# LEF file generated by Abstract Generator version 5.5.9 on Apr 28 16:11:38 2004
#
# Contains LEF for all bins.
# Options:   [ ] Antenna
#            [x] Geometry
#            [x] Technology

VERSION 5.7 ;
#NAMESCASESENSITIVE ON ;
BUSBITCHARS "[]" ;
DIVIDERCHAR "/" ;

PROPERTYDEFINITIONS
  LAYER LEF57_SPACING STRING ;
END PROPERTYDEFINITIONS

PROPERTYDEFINITIONS
  LAYER LEF57_SPACINGTABLE STRING ;
END PROPERTYDEFINITIONS

UNITS
  DATABASE MICRONS 2000 ;
END UNITS

USEMINSPACING OBS OFF ;
#USEMINSPACING PIN OFF ;
CLEARANCEMEASURE EUCLIDEAN ;

MANUFACTURINGGRID 0.005 ;

LAYER DIFF 
  TYPE MASTERSLICE ;
END DIFF 

LAYER PO1
  TYPE MASTERSLICE ;
END PO1

LAYER LLHVT
  TYPE IMPLANT ;
  SPACING 0.20  ;
  WIDTH 0.36 ;
END LLHVT

LAYER LLLVT
  TYPE IMPLANT ;
  SPACING 0.20  ;
  WIDTH 0.36 ;
END LLLVT

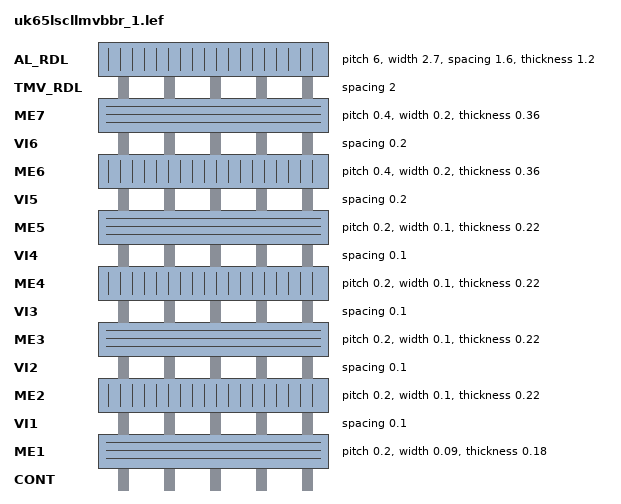
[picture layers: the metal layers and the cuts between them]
LAYER CONT
  TYPE CUT ;
  ANTENNAAREARATIO 10 ;
END CONT

LAYER ME1
  TYPE ROUTING ;
  DIRECTION HORIZONTAL ;
  PITCH 0.20 ;
  OFFSET 0.0 ;
  WIDTH 0.09 ;
  SPACINGTABLE PARALLELRUNLENGTH 0 0.5 2.8 WIDTH 0 0.09 0.09 0.09 WIDTH 0.5 0.09 0.16 0.16 WIDTH 2.8 0.09 0.16 0.3 ;
  MAXWIDTH 12 ;
  RESISTANCE RPERSQ 0.17 ;
  CAPACITANCE CPERSQDIST 3.0334e-04 ;
  EDGECAPACITANCE 1.0635e-04 ;
  THICKNESS 0.18 ;
  ANTENNACUMAREARATIO 5000 ;
  ANTENNACUMDIFFAREARATIO PWL ( ( 0 5000 ) ( 0.095 5000 ) ( 0.1 45045 ) ( 100 90000 ) ) ;
  AREA 0.042 ;
  MINENCLOSEDAREA 0.2 ;
  MINIMUMCUT 2 WIDTH 0.495 WITHIN 0.3 FROMABOVE ;
  MINIMUMCUT 3 WIDTH 0.7 WITHIN 0.3 FROMABOVE ;
  MINIMUMCUT 4 WIDTH 1.495 WITHIN 0.3 FROMABOVE ;
  MINIMUMDENSITY 15 ;
  MAXIMUMDENSITY 80 ;
  DENSITYCHECKWINDOW 50 50 ;
  DENSITYCHECKSTEP 25 ;
  FILLACTIVESPACING 0.8 ;
  MINSTEP 0.045 MAXEDGES 2 ;
  DCCURRENTDENSITY AVERAGE 1.89 ;
  ACCURRENTDENSITY RMS
   FREQUENCY	1 ;
   WIDTH	0.09 0.2 0.5 1.0 2.0 5.0 12.0 ;
   TABLEENTRIES	14.996 11.459 8.638 7.329 6.546 6.015 5.794 ;
END ME1

LAYER VI1
  TYPE CUT ;
  SPACING 0.1 ;
  SPACING 0.11 ADJACENTCUTS 3 WITHIN 0.14 ;
  ANTENNACUMAREARATIO 180 ;
  ANTENNACUMDIFFAREARATIO PWL ( ( 0 180 ) ( 0.095 180 ) ( 0.1 820 ) ( 100 20800 ) ) ;
  DCCURRENTDENSITY AVERAGE 25 ;
END VI1

LAYER ME2
  TYPE ROUTING ;
  DIRECTION VERTICAL ;
  PITCH 0.20 ;
  OFFSET 0.10 ;
  WIDTH 0.10 ;
  SPACINGTABLE PARALLELRUNLENGTH 0 0.5 1.5 WIDTH 0 0.1 0.1 0.1 WIDTH 0.5 0.1 0.16 0.16 WIDTH 2.8 0.1 0.16 0.3 ;
  MAXWIDTH 12 ;
  RESISTANCE RPERSQ 0.15 ;
  CAPACITANCE CPERSQDIST 3.6968e-04 ;
  EDGECAPACITANCE 9.1099e-05 ;
  THICKNESS 0.22 ;
  ANTENNACUMAREARATIO 5000 ;
  ANTENNACUMDIFFAREARATIO PWL ( ( 0 5000 ) ( 0.095 5000 ) ( 0.1 45045 ) ( 100 90000 ) ) ;
  AREA 0.046 ;
  MINENCLOSEDAREA 0.11 ;
  MINIMUMCUT 2 WIDTH 0.495 WITHIN 0.35 ;
  MINIMUMCUT 3 WIDTH 0.7 WITHIN 0.35 ;
  MINIMUMCUT 4 WIDTH 1.495 WITHIN 0.35 ;
  MINIMUMDENSITY 15 ;
  MAXIMUMDENSITY 80 ;
  DENSITYCHECKWINDOW 50 50 ;
  DENSITYCHECKSTEP 25 ;
  FILLACTIVESPACING 0.8 ;
  MINSTEP 0.05 MAXEDGES 2 ;
  DCCURRENTDENSITY AVERAGE 2.31 ;
  ACCURRENTDENSITY RMS
   FREQUENCY	1 ;
   WIDTH	0.1 0.2 0.5 1.0 2.0 5.0 12.0 ;
   TABLEENTRIES	13.518 10.696 7.906 6.544 5.698 5.107 4.854 ;
END ME2

LAYER VI2
  TYPE CUT ;
  SPACING 0.1 ;
  SPACING 0.11 ADJACENTCUTS 3 WITHIN 0.14 ;
  ANTENNACUMAREARATIO 180 ;
  ANTENNACUMDIFFAREARATIO PWL ( ( 0 180 ) ( 0.095 180 ) ( 0.1 820 ) ( 100 20800 ) ) ;
  DCCURRENTDENSITY AVERAGE 25 ;
END VI2

LAYER ME3
  TYPE ROUTING ;
  DIRECTION HORIZONTAL ;
  PITCH 0.20 ;
  OFFSET 0.0 ;
  WIDTH 0.10 ;
  SPACINGTABLE PARALLELRUNLENGTH 0 0.5 1.5 WIDTH 0 0.1 0.1 0.1 WIDTH 0.5 0.1 0.16 0.16 WIDTH 2.8 0.1 0.16 0.3 ;
  MAXWIDTH 12 ;
  RESISTANCE RPERSQ 0.15 ;
  CAPACITANCE CPERSQDIST 3.6968e-04 ;
  EDGECAPACITANCE 9.1106e-05 ;
  THICKNESS 0.22 ;
  ANTENNACUMAREARATIO 5000 ;
  ANTENNACUMDIFFAREARATIO PWL ( ( 0 5000 ) ( 0.095 5000 ) ( 0.1 45045 ) ( 100 90000 ) ) ;
  AREA 0.046 ;
  MINENCLOSEDAREA 0.11 ;
  MINIMUMCUT 2 WIDTH 0.495 WITHIN 0.35 ;
  MINIMUMCUT 3 WIDTH 0.7 WITHIN 0.35 ;
  MINIMUMCUT 4 WIDTH 1.495 WITHIN 0.35 ;
  MINIMUMDENSITY 15 ;
  MAXIMUMDENSITY 80 ;
  DENSITYCHECKWINDOW 50 50 ;
  DENSITYCHECKSTEP 25 ;
  FILLACTIVESPACING 0.8 ;
  MINSTEP 0.05 MAXEDGES 2 ;
  DCCURRENTDENSITY AVERAGE 2.31 ;
  ACCURRENTDENSITY RMS
   FREQUENCY	1 ;
   WIDTH	0.1 0.2 0.5 1.0 2.0 5.0 12.0 ;
   TABLEENTRIES	12.347 9.791 7.149 5.806 4.946 4.326 4.055 ;
END ME3

LAYER VI3
  TYPE CUT ;
  SPACING 0.1 ;
  SPACING 0.11 ADJACENTCUTS 3 WITHIN 0.14 ;
  ANTENNACUMAREARATIO 180 ;
  ANTENNACUMDIFFAREARATIO PWL ( ( 0 180 ) ( 0.095 180 ) ( 0.1 820 ) ( 100 20800 ) ) ;
  DCCURRENTDENSITY AVERAGE 25 ;
END VI3

LAYER ME4
  TYPE ROUTING ;
  DIRECTION VERTICAL ;
  PITCH 0.20 ;
  OFFSET 0.10 ;
  WIDTH 0.10 ;
  SPACINGTABLE PARALLELRUNLENGTH 0 0.5 1.5 WIDTH 0 0.1 0.1 0.1 WIDTH 0.5 0.1 0.16 0.16 WIDTH 2.8 0.1 0.16 0.3 ;
  MAXWIDTH 12 ;
  RESISTANCE RPERSQ 0.15 ;
  CAPACITANCE CPERSQDIST 3.6968e-04 ;
  EDGECAPACITANCE 9.1138e-05 ;
  THICKNESS 0.22 ;
  ANTENNACUMAREARATIO 5000 ;
  ANTENNACUMDIFFAREARATIO PWL ( ( 0 5000 ) ( 0.095 5000 ) ( 0.1 45045 ) ( 100 90000 ) ) ;
  AREA 0.046 ;
  MINENCLOSEDAREA 0.11 ;
  MINIMUMCUT 2 WIDTH 0.495 WITHIN 0.35 ;
  MINIMUMCUT 3 WIDTH 0.7 WITHIN 0.35 ;
  MINIMUMCUT 4 WIDTH 1.495 WITHIN 0.35 ;
  MINIMUMDENSITY 15 ;
  MAXIMUMDENSITY 80 ;
  DENSITYCHECKWINDOW 50 50 ;
  DENSITYCHECKSTEP 25 ;
  FILLACTIVESPACING 0.8 ;
  MINSTEP 0.05 MAXEDGES 2 ;
  DCCURRENTDENSITY AVERAGE 2.31 ;
  ACCURRENTDENSITY RMS
   FREQUENCY	1 ;
   WIDTH	0.1 0.2 0.5 1.0 2.0 5.0 12.0 ;
   TABLEENTRIES	11.641 9.262 6.716 5.383 4.507 3.862 3.574 ;
END ME4

LAYER VI4
  TYPE CUT ;
  SPACING 0.1 ;
  SPACING 0.11 ADJACENTCUTS 3 WITHIN 0.14 ;
#  SPACING 0.005 LAYER VI3 ; # for stacked via < 4
  ANTENNACUMAREARATIO 180 ;
  ANTENNACUMDIFFAREARATIO PWL ( ( 0 180 ) ( 0.095 180 ) ( 0.1 820 ) ( 100 20800 ) ) ;
  DCCURRENTDENSITY AVERAGE 25 ;
END VI4

LAYER ME5
  TYPE ROUTING ;
  DIRECTION HORIZONTAL ;
  PITCH 0.20 ;
  OFFSET 0.0 ;
  WIDTH 0.10 ;
  SPACINGTABLE PARALLELRUNLENGTH 0 0.5 1.5 WIDTH 0 0.1 0.1 0.1 WIDTH 0.5 0.1 0.16 0.16 WIDTH 2.8 0.1 0.16 0.3 ;
  MAXWIDTH 12 ;
  RESISTANCE RPERSQ 0.15 ;
  CAPACITANCE CPERSQDIST 2.9723e-04 ;
  EDGECAPACITANCE 9.9994e-05 ;
  THICKNESS 0.22 ;
  ANTENNACUMAREARATIO 5000 ;
  ANTENNACUMDIFFAREARATIO PWL ( ( 0 5000 ) ( 0.095 5000 ) ( 0.1 45045 ) ( 100 90000 ) ) ;
  AREA 0.046 ;
  MINENCLOSEDAREA 0.11 ;
  MINIMUMCUT 2 WIDTH 0.495 WITHIN 0.35 FROMBELOW ;
  MINIMUMCUT 3 WIDTH 0.7 WITHIN 0.35 FROMBELOW ;
  MINIMUMCUT 4 WIDTH 1.495 WITHIN 0.35 FROMBELOW ;
  MINIMUMCUT 2 WIDTH 0.995 WITHIN 0.6 FROMABOVE ; #
  MINIMUMCUT 3 WIDTH 1.395 WITHIN 0.6 FROMABOVE ; #
  MINIMUMCUT 4 WIDTH 2.995 WITHIN 0.6 FROMABOVE ; #
  MINIMUMDENSITY 15 ;
  MAXIMUMDENSITY 80 ;
  DENSITYCHECKWINDOW 50 50 ;
  DENSITYCHECKSTEP 25 ;
  FILLACTIVESPACING 0.8 ;
  MINSTEP 0.05 MAXEDGES 2 ;
  DCCURRENTDENSITY AVERAGE 2.31 ;
  ACCURRENTDENSITY RMS
   FREQUENCY	1 ;
   WIDTH	0.1 0.2 0.5 1.0 2.0 5.0 12.0 ;
   TABLEENTRIES	11.159 8.907 6.432 5.104 4.216 3.549 3.245 ;
END ME5

LAYER VI5
  TYPE CUT ;
  SPACING 0.2 ;
  ANTENNACUMAREARATIO 180 ;
  ANTENNACUMDIFFAREARATIO PWL ( ( 0 180 ) ( 0.095 180 ) ( 0.1 820 ) ( 100 20800 ) ) ;
  DCCURRENTDENSITY AVERAGE 9.75 ;
END VI5

LAYER ME6
  TYPE ROUTING ;
  DIRECTION VERTICAL ;
  PITCH 0.4 ;
  OFFSET 0.2 ;
  WIDTH 0.20 ;
  SPACINGTABLE PARALLELRUNLENGTH 0 1.5 4.5 WIDTH 0 0.2 0.2 0.2 WIDTH 2 0.2 0.35 0.35 WIDTH 8 0.2 0.35 0.84 ;
  MAXWIDTH 12 ;
  RESISTANCE RPERSQ 0.07 ;
  CAPACITANCE CPERSQDIST 2.2816e-04 ;
  EDGECAPACITANCE 1.0339e-04 ;
  THICKNESS 0.36 ;
  ANTENNACUMAREARATIO 5000 ;
  ANTENNACUMDIFFAREARATIO PWL ( ( 0 5000 ) ( 0.095 5000 ) ( 0.1 45045 ) ( 100 90000 ) ) ;
  AREA 0.10 ;
  MINENCLOSEDAREA 0.31 ;
  MINIMUMCUT 2 WIDTH 0.995 WITHIN 0.6 ;
  MINIMUMCUT 3 WIDTH 1.395 WITHIN 0.6 ;
  MINIMUMCUT 4 WIDTH 2.995 WITHIN 0.6 ;
  MINIMUMDENSITY 15 ;
  MAXIMUMDENSITY 80 ;
  DENSITYCHECKWINDOW 50 50 ;
  DENSITYCHECKSTEP 25 ;
  FILLACTIVESPACING 0.8 ;
  MINSTEP 0.10 MAXEDGES 2 ;
  DCCURRENTDENSITY AVERAGE 4.14 ;
  ACCURRENTDENSITY RMS
   FREQUENCY	1 ;
   WIDTH	0.2 0.4 1.0 3.0 12.0 ;
   TABLEENTRIES	10.586 8.398 6.122 4.478 3.604 ;
END ME6

LAYER VI6
  TYPE CUT ;
  SPACING 0.2 ;
  ANTENNACUMAREARATIO 180 ;
  ANTENNACUMDIFFAREARATIO PWL ( ( 0 180 ) ( 0.095 180 ) ( 0.1 820 ) ( 100 20800 ) ) ;
  DCCURRENTDENSITY AVERAGE 24 ;
END VI6

LAYER ME7
  TYPE ROUTING ;
  DIRECTION HORIZONTAL ;
  PITCH 0.4 ;
  OFFSET 0.0 ;
  WIDTH 0.2 ;
  SPACINGTABLE PARALLELRUNLENGTH 0 1.5 4.5 WIDTH 0 0.2 0.2 0.2 WIDTH 2 0.2 0.35 0.35 WIDTH 8 0.2 0.35 0.84 ;
  MAXWIDTH 12 ;
  RESISTANCE RPERSQ 0.07 ;
  CAPACITANCE CPERSQDIST 1.7444e-04 ;
  EDGECAPACITANCE 1.0795e-04 ;
  THICKNESS 0.36 ;
  ANTENNACUMAREARATIO 5000 ;
  ANTENNACUMDIFFAREARATIO PWL ( ( 0 5000 ) ( 0.095 5000 ) ( 0.1 45045 ) ( 100 90000 ) ) ;
  AREA 0.10 ;
  MINENCLOSEDAREA 0.31 ;
  MINIMUMCUT 2 WIDTH 0.995 WITHIN 0.6 FROMBELOW ;
  MINIMUMCUT 3 WIDTH 1.395 WITHIN 0.6 FROMBELOW ;
  MINIMUMCUT 4 WIDTH 2.995 WITHIN 0.6 FROMBELOW ;
  MINIMUMDENSITY 15 ;
  MAXIMUMDENSITY 80 ;
  DENSITYCHECKWINDOW 50 50 ;
  DENSITYCHECKSTEP 25 ;
  FILLACTIVESPACING 0.8 ;
  MINSTEP 0.10 MAXEDGES 2 ;
  DCCURRENTDENSITY AVERAGE 4.14 ;
  ACCURRENTDENSITY RMS
   FREQUENCY	1 ;
   WIDTH	0.2 0.4 1.0 3.0 12.0 ;
   TABLEENTRIES	10.542 8.384 6.076 4.358 3.414 ;
END ME7

LAYER TMV_RDL
  TYPE CUT ;
  SPACING 2.0 ;
  ANTENNAAREARATIO 80 ;
  ANTENNADIFFAREARATIO PWL ( ( 0 80 ) ( 0.095 80 ) ( 0.1 408.3 ) ( 100 8700 ) ) ;
  DCCURRENTDENSITY AVERAGE 0.728 ;
END TMV_RDL

LAYER AL_RDL
  TYPE ROUTING ;
  DIRECTION VERTICAL ;
  PITCH 6.0 ;
  OFFSET 3.0 ;
  WIDTH 2.7 ;
  SPACING 1.6 ;
  SPACING 3 RANGE 35.005 200 ;
  RESISTANCE RPERSQ 0.022 ;
  CAPACITANCE CPERSQDIST 3.6e-05 ;
  EDGECAPACITANCE 2.94e-04 ;
  THICKNESS 1.2 ;
  ANTENNASIDEAREARATIO 2000 ;
  ANTENNADIFFSIDEAREARATIO PWL ( ( 0 2000 ) ( 0.095 2000 ) ( 0.1 30800 ) ( 100 830000 ) ) ;
  MINIMUMDENSITY 10 ;
  MAXIMUMDENSITY 85 ;
  DCCURRENTDENSITY AVERAGE 2.09 ;
  ACCURRENTDENSITY RMS
   FREQUENCY	1 ;
   WIDTH	2.7 6 24 ;
   TABLEENTRIES	6.657 5.265 4.106 ;
END AL_RDL

MAXVIASTACK 4 ;

VIA VIA12 DEFAULT
  LAYER ME1 ;
  RECT -0.090 -0.050 0.090 0.050 ;
  LAYER VI1 ;
  RECT -0.050 -0.050 0.050 0.050 ;
  LAYER ME2 ;
  RECT -0.050 -0.090 0.050 0.090 ;
  RESISTANCE 2.0e+00 ;
END VIA12

VIA VIA23 DEFAULT
  LAYER ME2 ;
    RECT -0.050 -0.090 0.050 0.090 ;
  LAYER VI2 ;
    RECT -0.050 -0.050 0.050 0.050 ;
  LAYER ME3 ;
    RECT -0.090 -0.050 0.090 0.050 ;
  RESISTANCE 2.0e+00 ;
END VIA23

VIA VIA34 DEFAULT
  LAYER ME3 ;
    RECT -0.090 -0.050 0.090 0.050 ;
  LAYER VI3 ;
    RECT -0.050 -0.050 0.050 0.050 ;
  LAYER ME4 ;
    RECT -0.050 -0.090 0.050 0.090 ;
  RESISTANCE 2.0e+00 ;
END VIA34

VIA VIA45 DEFAULT
  LAYER ME4 ;
    RECT -0.090 -0.050 0.090 0.050 ;
  LAYER VI4 ;
    RECT -0.050 -0.050 0.050 0.050 ;
  LAYER ME5 ;
    RECT -0.050 -0.090 0.050 0.090 ;
  RESISTANCE 2.0e+00 ;
END VIA45

VIA VIA56 DEFAULT
  LAYER ME5 ;
    RECT -0.10 -0.130 0.10 0.130 ;
  LAYER VI5 ;
    RECT -0.10 -0.10 0.10 0.10 ;
  LAYER ME6 ;
    RECT -0.10 -0.10 0.10 0.10 ;
  RESISTANCE 8.0e-01 ;
END VIA56

VIA VIA67 DEFAULT
  LAYER ME6 ;
    RECT -0.130 -0.10 0.130 0.10 ;
  LAYER VI6 ;
    RECT -0.10 -0.10 0.10 0.10 ;
  LAYER ME7 ;
    RECT -0.10 -0.10 0.10 0.10 ;
  RESISTANCE 8.0e-01 ;
END VIA67

VIA VIA_TMV DEFAULT
  LAYER ME7 ;
    RECT -2.35 -2.35 2.35 2.35 ;
  LAYER TMV_RDL ;
    RECT -2.0 -2.0 2.0 2.0 ;
  LAYER AL_RDL ;
    RECT -2.5 -2.5 2.5 2.5 ;
  RESISTANCE 0.013 ;
END VIA_TMV



# vias generated from signal via rules

VIA V12_VV DEFAULT 
    LAYER ME1 ; 
	RECT -0.050000 -0.090000 0.050000 0.090000 ;
    LAYER VI1 ; 
	RECT -0.050000 -0.050000 0.050000 0.050000 ;
    LAYER ME2 ; 
	RECT -0.050000 -0.090000 0.050000 0.090000 ;
    RESISTANCE 2.000000 ;
END V12_VV
VIA V12_VH DEFAULT 
    LAYER ME1 ; 
	RECT -0.050000 -0.090000 0.050000 0.090000 ;
    LAYER VI1 ; 
	RECT -0.050000 -0.050000 0.050000 0.050000 ;
    LAYER ME2 ; 
	RECT -0.090000 -0.050000 0.090000 0.050000 ;
    RESISTANCE 2.000000 ;
END V12_VH
VIA V12_HH DEFAULT 
    LAYER ME1 ; 
	RECT -0.090000 -0.050000 0.090000 0.050000 ;
    LAYER VI1 ; 
	RECT -0.050000 -0.050000 0.050000 0.050000 ;
    LAYER ME2 ; 
	RECT -0.090000 -0.050000 0.090000 0.050000 ;
    RESISTANCE 2.000000 ;
END V12_HH
VIA V12_2x1_HV_E DEFAULT 
    LAYER ME1 ; 
	RECT -0.090000 -0.050000 0.290000 0.050000 ;
    LAYER VI1 ; 
	RECT -0.050000 -0.050000 0.050000 0.050000 ;
	RECT 0.150000 -0.050000 0.250000 0.050000 ;
    LAYER ME2 ; 
	RECT -0.050000 -0.090000 0.250000 0.090000 ;
    RESISTANCE 1.000000 ;
END V12_2x1_HV_E
VIA V12_2x1_HV_W DEFAULT 
    LAYER ME1 ; 
	RECT -0.290000 -0.050000 0.090000 0.050000 ;
    LAYER VI1 ; 
	RECT -0.250000 -0.050000 -0.150000 0.050000 ;
	RECT -0.050000 -0.050000 0.050000 0.050000 ;
    LAYER ME2 ; 
	RECT -0.250000 -0.090000 0.050000 0.090000 ;
    RESISTANCE 1.000000 ;
END V12_2x1_HV_W
VIA V12_1x2_HV_N DEFAULT 
    LAYER ME1 ; 
	RECT -0.090000 -0.050000 0.090000 0.250000 ;
    LAYER VI1 ; 
	RECT -0.050000 -0.050000 0.050000 0.050000 ;
	RECT -0.050000 0.150000 0.050000 0.250000 ;
    LAYER ME2 ; 
	RECT -0.050000 -0.090000 0.050000 0.290000 ;
    RESISTANCE 1.000000 ;
END V12_1x2_HV_N
VIA V12_1x2_HV_S DEFAULT 
    LAYER ME1 ; 
	RECT -0.090000 -0.250000 0.090000 0.050000 ;
    LAYER VI1 ; 
	RECT -0.050000 -0.250000 0.050000 -0.150000 ;
	RECT -0.050000 -0.050000 0.050000 0.050000 ;
    LAYER ME2 ; 
	RECT -0.050000 -0.290000 0.050000 0.090000 ;
    RESISTANCE 1.000000 ;
END V12_1x2_HV_S
VIA V12_3x1_HV_C DEFAULT 
    LAYER ME1 ; 
	RECT -0.290000 -0.050000 0.290000 0.050000 ;
    LAYER VI1 ; 
	RECT -0.250000 -0.050000 -0.150000 0.050000 ;
	RECT -0.050000 -0.050000 0.050000 0.050000 ;
	RECT 0.150000 -0.050000 0.250000 0.050000 ;
    LAYER ME2 ; 
	RECT -0.250000 -0.090000 0.250000 0.090000 ;
    RESISTANCE 0.666667 ;
END V12_3x1_HV_C
VIA V12_1x3_HV_C DEFAULT 
    LAYER ME1 ; 
	RECT -0.090000 -0.250000 0.090000 0.250000 ;
    LAYER VI1 ; 
	RECT -0.050000 -0.250000 0.050000 -0.150000 ;
	RECT -0.050000 -0.050000 0.050000 0.050000 ;
	RECT -0.050000 0.150000 0.050000 0.250000 ;
    LAYER ME2 ; 
	RECT -0.050000 -0.290000 0.050000 0.290000 ;
    RESISTANCE 0.666667 ;
END V12_1x3_HV_C
VIA V12_2x2_HV DEFAULT 
    LAYER ME1 ; 
	RECT -0.190000 -0.150000 0.190000 0.150000 ;
    LAYER VI1 ; 
	RECT -0.150000 -0.150000 -0.050000 -0.050000 ;
	RECT 0.050000 -0.150000 0.150000 -0.050000 ;
	RECT -0.150000 0.050000 -0.050000 0.150000 ;
	RECT 0.050000 0.050000 0.150000 0.150000 ;
    LAYER ME2 ; 
	RECT -0.150000 -0.190000 0.150000 0.190000 ;
    RESISTANCE 0.500000 ;
END V12_2x2_HV
VIA V23_HH DEFAULT 
    LAYER ME2 ; 
	RECT -0.090000 -0.050000 0.090000 0.050000 ;
    LAYER VI2 ; 
	RECT -0.050000 -0.050000 0.050000 0.050000 ;
    LAYER ME3 ; 
	RECT -0.090000 -0.050000 0.090000 0.050000 ;
    RESISTANCE 2.000000 ;
END V23_HH
VIA V23_HV DEFAULT 
    LAYER ME2 ; 
	RECT -0.090000 -0.050000 0.090000 0.050000 ;
    LAYER VI2 ; 
	RECT -0.050000 -0.050000 0.050000 0.050000 ;
    LAYER ME3 ; 
	RECT -0.050000 -0.090000 0.050000 0.090000 ;
    RESISTANCE 2.000000 ;
END V23_HV
VIA V23_VV DEFAULT 
    LAYER ME2 ; 
	RECT -0.050000 -0.090000 0.050000 0.090000 ;
    LAYER VI2 ; 
	RECT -0.050000 -0.050000 0.050000 0.050000 ;
    LAYER ME3 ; 
	RECT -0.050000 -0.090000 0.050000 0.090000 ;
    RESISTANCE 2.000000 ;
END V23_VV
VIA V23_M_NH DEFAULT 
    LAYER ME2 ; 
	RECT -0.050000 -0.090000 0.050000 0.370000 ;
    LAYER VI2 ; 
	RECT -0.050000 -0.050000 0.050000 0.050000 ;
    LAYER ME3 ; 
	RECT -0.090000 -0.050000 0.090000 0.050000 ;
    RESISTANCE 2.000000 ;
END V23_M_NH
VIA V23_M_SH DEFAULT 
    LAYER ME2 ; 
	RECT -0.050000 -0.370000 0.050000 0.090000 ;
    LAYER VI2 ; 
	RECT -0.050000 -0.050000 0.050000 0.050000 ;
    LAYER ME3 ; 
	RECT -0.090000 -0.050000 0.090000 0.050000 ;
    RESISTANCE 2.000000 ;
END V23_M_SH
VIA V23_2x1_VH_E DEFAULT 
    LAYER ME2 ; 
	RECT -0.050000 -0.090000 0.250000 0.090000 ;
    LAYER VI2 ; 
	RECT -0.050000 -0.050000 0.050000 0.050000 ;
	RECT 0.150000 -0.050000 0.250000 0.050000 ;
    LAYER ME3 ; 
	RECT -0.090000 -0.050000 0.290000 0.050000 ;
    RESISTANCE 1.000000 ;
END V23_2x1_VH_E
VIA V23_2x1_VH_W DEFAULT 
    LAYER ME2 ; 
	RECT -0.250000 -0.090000 0.050000 0.090000 ;
    LAYER VI2 ; 
	RECT -0.250000 -0.050000 -0.150000 0.050000 ;
	RECT -0.050000 -0.050000 0.050000 0.050000 ;
    LAYER ME3 ; 
	RECT -0.290000 -0.050000 0.090000 0.050000 ;
    RESISTANCE 1.000000 ;
END V23_2x1_VH_W
VIA V23_1x2_VH_N DEFAULT 
    LAYER ME2 ; 
	RECT -0.050000 -0.090000 0.050000 0.290000 ;
    LAYER VI2 ; 
	RECT -0.050000 -0.050000 0.050000 0.050000 ;
	RECT -0.050000 0.150000 0.050000 0.250000 ;
    LAYER ME3 ; 
	RECT -0.090000 -0.050000 0.090000 0.250000 ;
    RESISTANCE 1.000000 ;
END V23_1x2_VH_N
VIA V23_1x2_VH_S DEFAULT 
    LAYER ME2 ; 
	RECT -0.050000 -0.290000 0.050000 0.090000 ;
    LAYER VI2 ; 
	RECT -0.050000 -0.250000 0.050000 -0.150000 ;
	RECT -0.050000 -0.050000 0.050000 0.050000 ;
    LAYER ME3 ; 
	RECT -0.090000 -0.250000 0.090000 0.050000 ;
    RESISTANCE 1.000000 ;
END V23_1x2_VH_S
VIA V23_3x1_VH_C DEFAULT 
    LAYER ME2 ; 
	RECT -0.250000 -0.090000 0.250000 0.090000 ;
    LAYER VI2 ; 
	RECT -0.250000 -0.050000 -0.150000 0.050000 ;
	RECT -0.050000 -0.050000 0.050000 0.050000 ;
	RECT 0.150000 -0.050000 0.250000 0.050000 ;
    LAYER ME3 ; 
	RECT -0.290000 -0.050000 0.290000 0.050000 ;
    RESISTANCE 0.666667 ;
END V23_3x1_VH_C
VIA V23_1x3_VH_C DEFAULT 
    LAYER ME2 ; 
	RECT -0.050000 -0.290000 0.050000 0.290000 ;
    LAYER VI2 ; 
	RECT -0.050000 -0.250000 0.050000 -0.150000 ;
	RECT -0.050000 -0.050000 0.050000 0.050000 ;
	RECT -0.050000 0.150000 0.050000 0.250000 ;
    LAYER ME3 ; 
	RECT -0.090000 -0.250000 0.090000 0.250000 ;
    RESISTANCE 0.666667 ;
END V23_1x3_VH_C
VIA V23_2x2_VH DEFAULT 
    LAYER ME2 ; 
	RECT -0.150000 -0.190000 0.150000 0.190000 ;
    LAYER VI2 ; 
	RECT -0.150000 -0.150000 -0.050000 -0.050000 ;
	RECT 0.050000 -0.150000 0.150000 -0.050000 ;
	RECT -0.150000 0.050000 -0.050000 0.150000 ;
	RECT 0.050000 0.050000 0.150000 0.150000 ;
    LAYER ME3 ; 
	RECT -0.190000 -0.150000 0.190000 0.150000 ;
    RESISTANCE 0.500000 ;
END V23_2x2_VH
VIA V34_VV DEFAULT 
    LAYER ME3 ; 
	RECT -0.050000 -0.090000 0.050000 0.090000 ;
    LAYER VI3 ; 
	RECT -0.050000 -0.050000 0.050000 0.050000 ;
    LAYER ME4 ; 
	RECT -0.050000 -0.090000 0.050000 0.090000 ;
    RESISTANCE 2.000000 ;
END V34_VV
VIA V34_VH DEFAULT 
    LAYER ME3 ; 
	RECT -0.050000 -0.090000 0.050000 0.090000 ;
    LAYER VI3 ; 
	RECT -0.050000 -0.050000 0.050000 0.050000 ;
    LAYER ME4 ; 
	RECT -0.090000 -0.050000 0.090000 0.050000 ;
    RESISTANCE 2.000000 ;
END V34_VH
VIA V34_HH DEFAULT 
    LAYER ME3 ; 
	RECT -0.090000 -0.050000 0.090000 0.050000 ;
    LAYER VI3 ; 
	RECT -0.050000 -0.050000 0.050000 0.050000 ;
    LAYER ME4 ; 
	RECT -0.090000 -0.050000 0.090000 0.050000 ;
    RESISTANCE 2.000000 ;
END V34_HH
VIA V34_M_EV DEFAULT 
    LAYER ME3 ; 
	RECT -0.090000 -0.050000 0.370000 0.050000 ;
    LAYER VI3 ; 
	RECT -0.050000 -0.050000 0.050000 0.050000 ;
    LAYER ME4 ; 
	RECT -0.050000 -0.090000 0.050000 0.090000 ;
    RESISTANCE 2.000000 ;
END V34_M_EV
VIA V34_M_WV DEFAULT 
    LAYER ME3 ; 
	RECT -0.370000 -0.050000 0.090000 0.050000 ;
    LAYER VI3 ; 
	RECT -0.050000 -0.050000 0.050000 0.050000 ;
    LAYER ME4 ; 
	RECT -0.050000 -0.090000 0.050000 0.090000 ;
    RESISTANCE 2.000000 ;
END V34_M_WV
VIA V34_2x1_HV_E DEFAULT 
    LAYER ME3 ; 
	RECT -0.090000 -0.050000 0.290000 0.050000 ;
    LAYER VI3 ; 
	RECT -0.050000 -0.050000 0.050000 0.050000 ;
	RECT 0.150000 -0.050000 0.250000 0.050000 ;
    LAYER ME4 ; 
	RECT -0.050000 -0.090000 0.250000 0.090000 ;
    RESISTANCE 1.000000 ;
END V34_2x1_HV_E
VIA V34_2x1_HV_W DEFAULT 
    LAYER ME3 ; 
	RECT -0.290000 -0.050000 0.090000 0.050000 ;
    LAYER VI3 ; 
	RECT -0.250000 -0.050000 -0.150000 0.050000 ;
	RECT -0.050000 -0.050000 0.050000 0.050000 ;
    LAYER ME4 ; 
	RECT -0.250000 -0.090000 0.050000 0.090000 ;
    RESISTANCE 1.000000 ;
END V34_2x1_HV_W
VIA V34_1x2_HV_N DEFAULT 
    LAYER ME3 ; 
	RECT -0.090000 -0.050000 0.090000 0.250000 ;
    LAYER VI3 ; 
	RECT -0.050000 -0.050000 0.050000 0.050000 ;
	RECT -0.050000 0.150000 0.050000 0.250000 ;
    LAYER ME4 ; 
	RECT -0.050000 -0.090000 0.050000 0.290000 ;
    RESISTANCE 1.000000 ;
END V34_1x2_HV_N
VIA V34_1x2_HV_S DEFAULT 
    LAYER ME3 ; 
	RECT -0.090000 -0.250000 0.090000 0.050000 ;
    LAYER VI3 ; 
	RECT -0.050000 -0.250000 0.050000 -0.150000 ;
	RECT -0.050000 -0.050000 0.050000 0.050000 ;
    LAYER ME4 ; 
	RECT -0.050000 -0.290000 0.050000 0.090000 ;
    RESISTANCE 1.000000 ;
END V34_1x2_HV_S
VIA V34_3x1_HV_C DEFAULT 
    LAYER ME3 ; 
	RECT -0.290000 -0.050000 0.290000 0.050000 ;
    LAYER VI3 ; 
	RECT -0.250000 -0.050000 -0.150000 0.050000 ;
	RECT -0.050000 -0.050000 0.050000 0.050000 ;
	RECT 0.150000 -0.050000 0.250000 0.050000 ;
    LAYER ME4 ; 
	RECT -0.250000 -0.090000 0.250000 0.090000 ;
    RESISTANCE 0.666667 ;
END V34_3x1_HV_C
VIA V34_1x3_HV_C DEFAULT 
    LAYER ME3 ; 
	RECT -0.090000 -0.250000 0.090000 0.250000 ;
    LAYER VI3 ; 
	RECT -0.050000 -0.250000 0.050000 -0.150000 ;
	RECT -0.050000 -0.050000 0.050000 0.050000 ;
	RECT -0.050000 0.150000 0.050000 0.250000 ;
    LAYER ME4 ; 
	RECT -0.050000 -0.290000 0.050000 0.290000 ;
    RESISTANCE 0.666667 ;
END V34_1x3_HV_C
VIA V34_2x2_HV DEFAULT 
    LAYER ME3 ; 
	RECT -0.190000 -0.150000 0.190000 0.150000 ;
    LAYER VI3 ; 
	RECT -0.150000 -0.150000 -0.050000 -0.050000 ;
	RECT 0.050000 -0.150000 0.150000 -0.050000 ;
	RECT -0.150000 0.050000 -0.050000 0.150000 ;
	RECT 0.050000 0.050000 0.150000 0.150000 ;
    LAYER ME4 ; 
	RECT -0.150000 -0.190000 0.150000 0.190000 ;
    RESISTANCE 0.500000 ;
END V34_2x2_HV
VIA V45_VH DEFAULT 
    LAYER ME4 ; 
	RECT -0.050000 -0.090000 0.050000 0.090000 ;
    LAYER VI4 ; 
	RECT -0.050000 -0.050000 0.050000 0.050000 ;
    LAYER ME5 ; 
	RECT -0.090000 -0.050000 0.090000 0.050000 ;
    RESISTANCE 2.000000 ;
END V45_VH
VIA V45_HH DEFAULT 
    LAYER ME4 ; 
	RECT -0.090000 -0.050000 0.090000 0.050000 ;
    LAYER VI4 ; 
	RECT -0.050000 -0.050000 0.050000 0.050000 ;
    LAYER ME5 ; 
	RECT -0.090000 -0.050000 0.090000 0.050000 ;
    RESISTANCE 2.000000 ;
END V45_HH
VIA V45_VV DEFAULT 
    LAYER ME4 ; 
	RECT -0.050000 -0.090000 0.050000 0.090000 ;
    LAYER VI4 ; 
	RECT -0.050000 -0.050000 0.050000 0.050000 ;
    LAYER ME5 ; 
	RECT -0.050000 -0.090000 0.050000 0.090000 ;
    RESISTANCE 2.000000 ;
END V45_VV
VIA V45_M_NH DEFAULT 
    LAYER ME4 ; 
	RECT -0.050000 -0.090000 0.050000 0.370000 ;
    LAYER VI4 ; 
	RECT -0.050000 -0.050000 0.050000 0.050000 ;
    LAYER ME5 ; 
	RECT -0.090000 -0.050000 0.090000 0.050000 ;
    RESISTANCE 2.000000 ;
END V45_M_NH
VIA V45_M_SH DEFAULT 
    LAYER ME4 ; 
	RECT -0.050000 -0.370000 0.050000 0.090000 ;
    LAYER VI4 ; 
	RECT -0.050000 -0.050000 0.050000 0.050000 ;
    LAYER ME5 ; 
	RECT -0.090000 -0.050000 0.090000 0.050000 ;
    RESISTANCE 2.000000 ;
END V45_M_SH
VIA V45_2x1_VH_E DEFAULT 
    LAYER ME4 ; 
	RECT -0.050000 -0.090000 0.250000 0.090000 ;
    LAYER VI4 ; 
	RECT -0.050000 -0.050000 0.050000 0.050000 ;
	RECT 0.150000 -0.050000 0.250000 0.050000 ;
    LAYER ME5 ; 
	RECT -0.090000 -0.050000 0.290000 0.050000 ;
    RESISTANCE 1.000000 ;
END V45_2x1_VH_E
VIA V45_2x1_VH_W DEFAULT 
    LAYER ME4 ; 
	RECT -0.250000 -0.090000 0.050000 0.090000 ;
    LAYER VI4 ; 
	RECT -0.250000 -0.050000 -0.150000 0.050000 ;
	RECT -0.050000 -0.050000 0.050000 0.050000 ;
    LAYER ME5 ; 
	RECT -0.290000 -0.050000 0.090000 0.050000 ;
    RESISTANCE 1.000000 ;
END V45_2x1_VH_W
VIA V45_1x2_VH_N DEFAULT 
    LAYER ME4 ; 
	RECT -0.050000 -0.090000 0.050000 0.290000 ;
    LAYER VI4 ; 
	RECT -0.050000 -0.050000 0.050000 0.050000 ;
	RECT -0.050000 0.150000 0.050000 0.250000 ;
    LAYER ME5 ; 
	RECT -0.090000 -0.050000 0.090000 0.250000 ;
    RESISTANCE 1.000000 ;
END V45_1x2_VH_N
VIA V45_1x2_VH_S DEFAULT 
    LAYER ME4 ; 
	RECT -0.050000 -0.290000 0.050000 0.090000 ;
    LAYER VI4 ; 
	RECT -0.050000 -0.250000 0.050000 -0.150000 ;
	RECT -0.050000 -0.050000 0.050000 0.050000 ;
    LAYER ME5 ; 
	RECT -0.090000 -0.250000 0.090000 0.050000 ;
    RESISTANCE 1.000000 ;
END V45_1x2_VH_S
VIA V45_3x1_VH_C DEFAULT 
    LAYER ME4 ; 
	RECT -0.250000 -0.090000 0.250000 0.090000 ;
    LAYER VI4 ; 
	RECT -0.250000 -0.050000 -0.150000 0.050000 ;
	RECT -0.050000 -0.050000 0.050000 0.050000 ;
	RECT 0.150000 -0.050000 0.250000 0.050000 ;
    LAYER ME5 ; 
	RECT -0.290000 -0.050000 0.290000 0.050000 ;
    RESISTANCE 0.666667 ;
END V45_3x1_VH_C
VIA V45_1x3_VH_C DEFAULT 
    LAYER ME4 ; 
	RECT -0.050000 -0.290000 0.050000 0.290000 ;
    LAYER VI4 ; 
	RECT -0.050000 -0.250000 0.050000 -0.150000 ;
	RECT -0.050000 -0.050000 0.050000 0.050000 ;
	RECT -0.050000 0.150000 0.050000 0.250000 ;
    LAYER ME5 ; 
	RECT -0.090000 -0.250000 0.090000 0.250000 ;
    RESISTANCE 0.666667 ;
END V45_1x3_VH_C
VIA V45_2x2_VH DEFAULT 
    LAYER ME4 ; 
	RECT -0.150000 -0.190000 0.150000 0.190000 ;
    LAYER VI4 ; 
	RECT -0.150000 -0.150000 -0.050000 -0.050000 ;
	RECT 0.050000 -0.150000 0.150000 -0.050000 ;
	RECT -0.150000 0.050000 -0.050000 0.150000 ;
	RECT 0.050000 0.050000 0.150000 0.150000 ;
    LAYER ME5 ; 
	RECT -0.190000 -0.150000 0.190000 0.150000 ;
    RESISTANCE 0.500000 ;
END V45_2x2_VH
VIA V56_HV DEFAULT 
    LAYER ME5 ; 
	RECT -0.130000 -0.100000 0.130000 0.100000 ;
    LAYER VI5 ; 
	RECT -0.100000 -0.100000 0.100000 0.100000 ;
    LAYER ME6 ; 
	RECT -0.100000 -0.100000 0.100000 0.100000 ;
    RESISTANCE 0.800000 ;
END V56_HV
VIA V56_2x1_HV_E DEFAULT 
    LAYER ME5 ; 
	RECT -0.130000 -0.100000 0.530000 0.100000 ;
    LAYER VI5 ; 
	RECT -0.100000 -0.100000 0.100000 0.100000 ;
	RECT 0.300000 -0.100000 0.500000 0.100000 ;
    LAYER ME6 ; 
	RECT -0.100000 -0.100000 0.500000 0.100000 ;
    RESISTANCE 0.400000 ;
END V56_2x1_HV_E
VIA V56_2x1_HV_W DEFAULT 
    LAYER ME5 ; 
	RECT -0.530000 -0.100000 0.130000 0.100000 ;
    LAYER VI5 ; 
	RECT -0.500000 -0.100000 -0.300000 0.100000 ;
	RECT -0.100000 -0.100000 0.100000 0.100000 ;
    LAYER ME6 ; 
	RECT -0.500000 -0.100000 0.100000 0.100000 ;
    RESISTANCE 0.400000 ;
END V56_2x1_HV_W
VIA V56_1x2_HV_N DEFAULT 
    LAYER ME5 ; 
	RECT -0.130000 -0.100000 0.130000 0.500000 ;
    LAYER VI5 ; 
	RECT -0.100000 -0.100000 0.100000 0.100000 ;
	RECT -0.100000 0.300000 0.100000 0.500000 ;
    LAYER ME6 ; 
	RECT -0.100000 -0.100000 0.100000 0.500000 ;
    RESISTANCE 0.400000 ;
END V56_1x2_HV_N
VIA V56_1x2_HV_S DEFAULT 
    LAYER ME5 ; 
	RECT -0.130000 -0.500000 0.130000 0.100000 ;
    LAYER VI5 ; 
	RECT -0.100000 -0.500000 0.100000 -0.300000 ;
	RECT -0.100000 -0.100000 0.100000 0.100000 ;
    LAYER ME6 ; 
	RECT -0.100000 -0.500000 0.100000 0.100000 ;
    RESISTANCE 0.400000 ;
END V56_1x2_HV_S
VIA V56_3x1_HV_C DEFAULT 
    LAYER ME5 ; 
	RECT -0.530000 -0.100000 0.530000 0.100000 ;
    LAYER VI5 ; 
	RECT -0.500000 -0.100000 -0.300000 0.100000 ;
	RECT -0.100000 -0.100000 0.100000 0.100000 ;
	RECT 0.300000 -0.100000 0.500000 0.100000 ;
    LAYER ME6 ; 
	RECT -0.500000 -0.100000 0.500000 0.100000 ;
    RESISTANCE 0.266667 ;
END V56_3x1_HV_C
VIA V56_1x3_HV_C DEFAULT 
    LAYER ME5 ; 
	RECT -0.130000 -0.500000 0.130000 0.500000 ;
    LAYER VI5 ; 
	RECT -0.100000 -0.500000 0.100000 -0.300000 ;
	RECT -0.100000 -0.100000 0.100000 0.100000 ;
	RECT -0.100000 0.300000 0.100000 0.500000 ;
    LAYER ME6 ; 
	RECT -0.100000 -0.500000 0.100000 0.500000 ;
    RESISTANCE 0.266667 ;
END V56_1x3_HV_C
VIA V56_2x2_HV DEFAULT 
    LAYER ME5 ; 
	RECT -0.330000 -0.300000 0.330000 0.300000 ;
    LAYER VI5 ; 
	RECT -0.300000 -0.300000 -0.100000 -0.100000 ;
	RECT 0.100000 -0.300000 0.300000 -0.100000 ;
	RECT -0.300000 0.100000 -0.100000 0.300000 ;
	RECT 0.100000 0.100000 0.300000 0.300000 ;
    LAYER ME6 ; 
	RECT -0.300000 -0.300000 0.300000 0.300000 ;
    RESISTANCE 0.200000 ;
END V56_2x2_HV
VIA V67_VH DEFAULT 
    LAYER ME6 ; 
	RECT -0.100000 -0.130000 0.100000 0.130000 ;
    LAYER VI6 ; 
	RECT -0.100000 -0.100000 0.100000 0.100000 ;
    LAYER ME7 ; 
	RECT -0.100000 -0.100000 0.100000 0.100000 ;
    RESISTANCE 0.800000 ;
END V67_VH
VIA V67_M_NH DEFAULT 
    LAYER ME6 ; 
	RECT -0.100000 -0.130000 0.100000 0.370000 ;
    LAYER VI6 ; 
	RECT -0.100000 -0.100000 0.100000 0.100000 ;
    LAYER ME7 ; 
	RECT -0.100000 -0.100000 0.100000 0.100000 ;
    RESISTANCE 0.800000 ;
END V67_M_NH
VIA V67_M_SH DEFAULT 
    LAYER ME6 ; 
	RECT -0.100000 -0.370000 0.100000 0.130000 ;
    LAYER VI6 ; 
	RECT -0.100000 -0.100000 0.100000 0.100000 ;
    LAYER ME7 ; 
	RECT -0.100000 -0.100000 0.100000 0.100000 ;
    RESISTANCE 0.800000 ;
END V67_M_SH
VIA V67_2x1_VH_E DEFAULT 
    LAYER ME6 ; 
	RECT -0.100000 -0.130000 0.500000 0.130000 ;
    LAYER VI6 ; 
	RECT -0.100000 -0.100000 0.100000 0.100000 ;
	RECT 0.300000 -0.100000 0.500000 0.100000 ;
    LAYER ME7 ; 
	RECT -0.100000 -0.100000 0.500000 0.100000 ;
    RESISTANCE 0.400000 ;
END V67_2x1_VH_E
VIA V67_2x1_VH_W DEFAULT 
    LAYER ME6 ; 
	RECT -0.500000 -0.130000 0.100000 0.130000 ;
    LAYER VI6 ; 
	RECT -0.500000 -0.100000 -0.300000 0.100000 ;
	RECT -0.100000 -0.100000 0.100000 0.100000 ;
    LAYER ME7 ; 
	RECT -0.500000 -0.100000 0.100000 0.100000 ;
    RESISTANCE 0.400000 ;
END V67_2x1_VH_W
VIA V67_1x2_VH_N DEFAULT 
    LAYER ME6 ; 
	RECT -0.100000 -0.130000 0.100000 0.530000 ;
    LAYER VI6 ; 
	RECT -0.100000 -0.100000 0.100000 0.100000 ;
	RECT -0.100000 0.300000 0.100000 0.500000 ;
    LAYER ME7 ; 
	RECT -0.100000 -0.100000 0.100000 0.500000 ;
    RESISTANCE 0.400000 ;
END V67_1x2_VH_N
VIA V67_1x2_VH_S DEFAULT 
    LAYER ME6 ; 
	RECT -0.100000 -0.530000 0.100000 0.130000 ;
    LAYER VI6 ; 
	RECT -0.100000 -0.500000 0.100000 -0.300000 ;
	RECT -0.100000 -0.100000 0.100000 0.100000 ;
    LAYER ME7 ; 
	RECT -0.100000 -0.500000 0.100000 0.100000 ;
    RESISTANCE 0.400000 ;
END V67_1x2_VH_S
VIA V67_3x1_VH_C DEFAULT 
    LAYER ME6 ; 
	RECT -0.500000 -0.130000 0.500000 0.130000 ;
    LAYER VI6 ; 
	RECT -0.500000 -0.100000 -0.300000 0.100000 ;
	RECT -0.100000 -0.100000 0.100000 0.100000 ;
	RECT 0.300000 -0.100000 0.500000 0.100000 ;
    LAYER ME7 ; 
	RECT -0.500000 -0.100000 0.500000 0.100000 ;
    RESISTANCE 0.266667 ;
END V67_3x1_VH_C
VIA V67_1x3_VH_C DEFAULT 
    LAYER ME6 ; 
	RECT -0.100000 -0.530000 0.100000 0.530000 ;
    LAYER VI6 ; 
	RECT -0.100000 -0.500000 0.100000 -0.300000 ;
	RECT -0.100000 -0.100000 0.100000 0.100000 ;
	RECT -0.100000 0.300000 0.100000 0.500000 ;
    LAYER ME7 ; 
	RECT -0.100000 -0.500000 0.100000 0.500000 ;
    RESISTANCE 0.266667 ;
END V67_1x3_VH_C
VIA V67_2x2_VH DEFAULT 
    LAYER ME6 ; 
	RECT -0.300000 -0.330000 0.300000 0.330000 ;
    LAYER VI6 ; 
	RECT -0.300000 -0.300000 -0.100000 -0.100000 ;
	RECT 0.100000 -0.300000 0.300000 -0.100000 ;
	RECT -0.300000 0.100000 -0.100000 0.300000 ;
	RECT 0.100000 0.100000 0.300000 0.300000 ;
    LAYER ME7 ; 
	RECT -0.300000 -0.300000 0.300000 0.300000 ;
    RESISTANCE 0.200000 ;
END V67_2x2_VH
VIA V78_2x1_HV_E DEFAULT 
    LAYER ME7 ; 
	RECT -2.350000 -2.350000 8.350000 2.350000 ;
    LAYER TMV_RDL ; 
	RECT -2.000000 -2.000000 2.000000 2.000000 ;
	RECT 4.000000 -2.000000 8.000000 2.000000 ;
    LAYER AL_RDL ; 
	RECT -2.500000 -2.500000 8.500000 2.500000 ;
    RESISTANCE 0.006500 ;
END V78_2x1_HV_E
VIA V78_2x1_HV_W DEFAULT 
    LAYER ME7 ; 
	RECT -8.350000 -2.350000 2.350000 2.350000 ;
    LAYER TMV_RDL ; 
	RECT -8.000000 -2.000000 -4.000000 2.000000 ;
	RECT -2.000000 -2.000000 2.000000 2.000000 ;
    LAYER AL_RDL ; 
	RECT -8.500000 -2.500000 2.500000 2.500000 ;
    RESISTANCE 0.006500 ;
END V78_2x1_HV_W
VIA V78_1x2_HV_N DEFAULT 
    LAYER ME7 ; 
	RECT -2.350000 -2.350000 2.350000 8.350000 ;
    LAYER TMV_RDL ; 
	RECT -2.000000 -2.000000 2.000000 2.000000 ;
	RECT -2.000000 4.000000 2.000000 8.000000 ;
    LAYER AL_RDL ; 
	RECT -2.500000 -2.500000 2.500000 8.500000 ;
    RESISTANCE 0.006500 ;
END V78_1x2_HV_N
VIA V78_1x2_HV_S DEFAULT 
    LAYER ME7 ; 
	RECT -2.350000 -8.350000 2.350000 2.350000 ;
    LAYER TMV_RDL ; 
	RECT -2.000000 -8.000000 2.000000 -4.000000 ;
	RECT -2.000000 -2.000000 2.000000 2.000000 ;
    LAYER AL_RDL ; 
	RECT -2.500000 -8.500000 2.500000 2.500000 ;
    RESISTANCE 0.006500 ;
END V78_1x2_HV_S
VIA V78_3x1_HV_C DEFAULT 
    LAYER ME7 ; 
	RECT -8.350000 -2.350000 8.350000 2.350000 ;
    LAYER TMV_RDL ; 
	RECT -8.000000 -2.000000 -4.000000 2.000000 ;
	RECT -2.000000 -2.000000 2.000000 2.000000 ;
	RECT 4.000000 -2.000000 8.000000 2.000000 ;
    LAYER AL_RDL ; 
	RECT -8.500000 -2.500000 8.500000 2.500000 ;
    RESISTANCE 0.004333 ;
END V78_3x1_HV_C
VIA V78_1x3_HV_C DEFAULT 
    LAYER ME7 ; 
	RECT -2.350000 -8.350000 2.350000 8.350000 ;
    LAYER TMV_RDL ; 
	RECT -2.000000 -8.000000 2.000000 -4.000000 ;
	RECT -2.000000 -2.000000 2.000000 2.000000 ;
	RECT -2.000000 4.000000 2.000000 8.000000 ;
    LAYER AL_RDL ; 
	RECT -2.500000 -8.500000 2.500000 8.500000 ;
    RESISTANCE 0.004333 ;
END V78_1x3_HV_C
VIA V78_2x2_HV DEFAULT 
    LAYER ME7 ; 
	RECT -5.350000 -5.350000 5.350000 5.350000 ;
    LAYER TMV_RDL ; 
	RECT -5.000000 -5.000000 -1.000000 -1.000000 ;
	RECT 1.000000 -5.000000 5.000000 -1.000000 ;
	RECT -5.000000 1.000000 -1.000000 5.000000 ;
	RECT 1.000000 1.000000 5.000000 5.000000 ;
    LAYER AL_RDL ; 
	RECT -5.500000 -5.500000 5.500000 5.500000 ;
    RESISTANCE 0.003250 ;
END V78_2x2_HV

# end auto generated vias

VIARULE genm1m2 GENERATE
  LAYER ME1 ;
    ENCLOSURE 0.03 0 ;
  LAYER ME2 ;
    ENCLOSURE 0.03 0 ;
  LAYER VI1 ;
    RECT -0.05 -0.05 0.05 0.05 ;
    SPACING 0.24 BY 0.24 ;
END genm1m2

VIARULE genm2m3 GENERATE
  LAYER ME2 ;
    ENCLOSURE 0.03 0 ;
  LAYER ME3 ;
    ENCLOSURE 0.03 0 ;
  LAYER VI2 ;
    RECT -0.05 -0.05 0.05 0.05 ;
    SPACING 0.24 BY 0.24 ;
END genm2m3

VIARULE genm3m4 GENERATE
  LAYER ME3 ;
    ENCLOSURE 0.03 0 ;
  LAYER ME4 ;
    ENCLOSURE 0.03 0 ;
  LAYER VI3 ;
    RECT -0.05 -0.05 0.05 0.05 ;
    SPACING 0.24 BY 0.24 ;
END genm3m4

VIARULE genm4m5 GENERATE
  LAYER ME4 ;
    ENCLOSURE 0.03 0 ;
  LAYER ME5 ;
    ENCLOSURE 0.03 0 ;
  LAYER VI4 ;
    RECT -0.05 -0.05 0.05 0.05 ;
    SPACING 0.24 BY 0.24 ;
END genm4m5

VIARULE genm5m6 GENERATE
  LAYER ME5 ;
    ENCLOSURE 0.03 0 ;
  LAYER ME6 ;
    ENCLOSURE 0 0 ;
  LAYER VI5 ;
    RECT -0.10 -0.10 0.10 0.10 ;
    SPACING 0.40 BY 0.40 ;
END genm5m6

VIARULE genm6m7 GENERATE
  LAYER ME6 ;
    ENCLOSURE 0.03 0 ;
  LAYER ME7 ;
    ENCLOSURE 0 0 ;
  LAYER VI6 ;
    RECT -0.10 -0.10 0.10 0.10 ;
    SPACING 0.40 BY 0.40 ;
END genm6m7

VIARULE genm7mAL_RDL GENERATE
  LAYER ME7 ;
    ENCLOSURE 0.35 0.35 ;
  LAYER AL_RDL ;
    ENCLOSURE 0.5 0.5 ;
  LAYER TMV_RDL ;
    RECT -2.0 -2.0 2.0 2.0 ;
    SPACING 6.0 BY 6.0 ;
END genm7mAL_RDL


SITE CORE
  CLASS core ;
  SYMMETRY Y ;
  SIZE 0.2 BY 1.8 ;
END CORE

END LIBRARY
